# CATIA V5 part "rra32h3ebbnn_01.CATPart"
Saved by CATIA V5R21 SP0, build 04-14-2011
Part number: rra32h3ebbnn_01
Bounding box of the stored display mesh (mm): x 8.7 to 10.681, y -1.905 to 1.905, z -16.002 to -2.315
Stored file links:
  C:\TPO v2\SharedFS\Outgoing\rra32h3ebbnn_01.CATPart

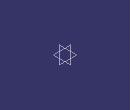
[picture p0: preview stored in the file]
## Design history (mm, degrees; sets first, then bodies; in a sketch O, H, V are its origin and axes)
AxisSystem1: origin (0, 0, 0), X (1, 0, 0), Y (0, 1, 0), Z (0, 0, 1)
Body1 "rra32h3ebbnn_01" (main body)
  Solid1: solid without history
